VERSION 5.7 ;
  NOWIREEXTENSIONATPIN ON ;
  DIVIDERCHAR "/" ;
  BUSBITCHARS "[]" ;
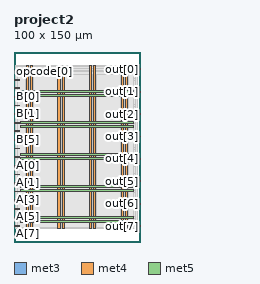
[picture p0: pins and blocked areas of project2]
MACRO project2
  CLASS BLOCK ;
  FOREIGN project2 ;
  ORIGIN 0.000 0.000 ;
  SIZE 100.000 BY 150.000 ;
  PIN A[0]
    DIRECTION INPUT ;
    USE SIGNAL ;
    ANTENNAGATEAREA 0.213000 ;
    PORT
      LAYER met3 ;
        RECT 0.000 59.880 4.000 60.480 ;
    END
  END A[0]
  PIN A[1]
    DIRECTION INPUT ;
    USE SIGNAL ;
    ANTENNAGATEAREA 0.213000 ;
    PORT
      LAYER met3 ;
        RECT 0.000 53.080 4.000 53.680 ;
    END
  END A[1]
  PIN A[2]
    DIRECTION INPUT ;
    USE SIGNAL ;
    ANTENNAGATEAREA 0.213000 ;
    PORT
      LAYER met3 ;
        RECT 0.000 46.280 4.000 46.880 ;
    END
  END A[2]
  PIN A[3]
    DIRECTION INPUT ;
    USE SIGNAL ;
    ANTENNAGATEAREA 0.213000 ;
    PORT
      LAYER met3 ;
        RECT 0.000 39.480 4.000 40.080 ;
    END
  END A[3]
  PIN A[4]
    DIRECTION INPUT ;
    USE SIGNAL ;
    ANTENNAGATEAREA 0.247500 ;
    PORT
      LAYER met3 ;
        RECT 0.000 32.680 4.000 33.280 ;
    END
  END A[4]
  PIN A[5]
    DIRECTION INPUT ;
    USE SIGNAL ;
    ANTENNAGATEAREA 0.247500 ;
    PORT
      LAYER met3 ;
        RECT 0.000 25.880 4.000 26.480 ;
    END
  END A[5]
  PIN A[6]
    DIRECTION INPUT ;
    USE SIGNAL ;
    ANTENNAGATEAREA 0.426000 ;
    PORT
      LAYER met3 ;
        RECT 0.000 19.080 4.000 19.680 ;
    END
  END A[6]
  PIN A[7]
    DIRECTION INPUT ;
    USE SIGNAL ;
    ANTENNAGATEAREA 0.213000 ;
    PORT
      LAYER met3 ;
        RECT 0.000 12.280 4.000 12.880 ;
    END
  END A[7]
  PIN B[0]
    DIRECTION INPUT ;
    USE SIGNAL ;
    ANTENNAGATEAREA 0.742500 ;
    PORT
      LAYER met3 ;
        RECT 0.000 114.280 4.000 114.880 ;
    END
  END B[0]
  PIN B[1]
    DIRECTION INPUT ;
    USE SIGNAL ;
    ANTENNAGATEAREA 0.495000 ;
    PORT
      LAYER met3 ;
        RECT 0.000 107.480 4.000 108.080 ;
    END
  END B[1]
  PIN B[2]
    DIRECTION INPUT ;
    USE SIGNAL ;
    ANTENNAGATEAREA 0.213000 ;
    PORT
      LAYER met3 ;
        RECT 0.000 100.680 4.000 101.280 ;
    END
  END B[2]
  PIN B[3]
    DIRECTION INPUT ;
    USE SIGNAL ;
    ANTENNAGATEAREA 0.213000 ;
    PORT
      LAYER met3 ;
        RECT 0.000 93.880 4.000 94.480 ;
    END
  END B[3]
  PIN B[4]
    DIRECTION INPUT ;
    USE SIGNAL ;
    ANTENNAGATEAREA 0.213000 ;
    PORT
      LAYER met3 ;
        RECT 0.000 87.080 4.000 87.680 ;
    END
  END B[4]
  PIN B[5]
    DIRECTION INPUT ;
    USE SIGNAL ;
    ANTENNAGATEAREA 0.247500 ;
    PORT
      LAYER met3 ;
        RECT 0.000 80.280 4.000 80.880 ;
    END
  END B[5]
  PIN B[6]
    DIRECTION INPUT ;
    USE SIGNAL ;
    ANTENNAGATEAREA 0.247500 ;
    PORT
      LAYER met3 ;
        RECT 0.000 73.480 4.000 74.080 ;
    END
  END B[6]
  PIN B[7]
    DIRECTION INPUT ;
    USE SIGNAL ;
    ANTENNAGATEAREA 0.213000 ;
    PORT
      LAYER met3 ;
        RECT 0.000 66.680 4.000 67.280 ;
    END
  END B[7]
  PIN VGND
    DIRECTION INOUT ;
    USE GROUND ;
    PORT
      LAYER met4 ;
        RECT 13.020 10.640 14.620 138.960 ;
    END
    PORT
      LAYER met4 ;
        RECT 38.020 10.640 39.620 138.960 ;
    END
    PORT
      LAYER met4 ;
        RECT 63.020 10.640 64.620 138.960 ;
    END
    PORT
      LAYER met4 ;
        RECT 88.020 10.640 89.620 138.960 ;
    END
    PORT
      LAYER met5 ;
        RECT 5.280 18.380 94.540 19.980 ;
    END
    PORT
      LAYER met5 ;
        RECT 5.280 43.380 94.540 44.980 ;
    END
    PORT
      LAYER met5 ;
        RECT 5.280 68.380 94.540 69.980 ;
    END
    PORT
      LAYER met5 ;
        RECT 5.280 93.380 94.540 94.980 ;
    END
    PORT
      LAYER met5 ;
        RECT 5.280 118.380 94.540 119.980 ;
    END
  END VGND
  PIN VPWR
    DIRECTION INOUT ;
    USE POWER ;
    PORT
      LAYER met4 ;
        RECT 9.720 10.640 11.320 138.960 ;
    END
    PORT
      LAYER met4 ;
        RECT 34.720 10.640 36.320 138.960 ;
    END
    PORT
      LAYER met4 ;
        RECT 59.720 10.640 61.320 138.960 ;
    END
    PORT
      LAYER met4 ;
        RECT 84.720 10.640 86.320 138.960 ;
    END
    PORT
      LAYER met5 ;
        RECT 5.280 15.080 94.540 16.680 ;
    END
    PORT
      LAYER met5 ;
        RECT 5.280 40.080 94.540 41.680 ;
    END
    PORT
      LAYER met5 ;
        RECT 5.280 65.080 94.540 66.680 ;
    END
    PORT
      LAYER met5 ;
        RECT 5.280 90.080 94.540 91.680 ;
    END
    PORT
      LAYER met5 ;
        RECT 5.280 115.080 94.540 116.680 ;
    END
  END VPWR
  PIN opcode[0]
    DIRECTION INPUT ;
    USE SIGNAL ;
    ANTENNAGATEAREA 0.247500 ;
    PORT
      LAYER met3 ;
        RECT 0.000 134.680 4.000 135.280 ;
    END
  END opcode[0]
  PIN opcode[1]
    DIRECTION INPUT ;
    USE SIGNAL ;
    ANTENNAGATEAREA 0.213000 ;
    PORT
      LAYER met3 ;
        RECT 0.000 127.880 4.000 128.480 ;
    END
  END opcode[1]
  PIN opcode[2]
    DIRECTION INPUT ;
    USE SIGNAL ;
    ANTENNAGATEAREA 0.213000 ;
    PORT
      LAYER met3 ;
        RECT 0.000 121.080 4.000 121.680 ;
    END
  END opcode[2]
  PIN out[0]
    DIRECTION OUTPUT ;
    USE SIGNAL ;
    ANTENNADIFFAREA 0.445500 ;
    PORT
      LAYER met3 ;
        RECT 96.000 136.040 100.000 136.640 ;
    END
  END out[0]
  PIN out[1]
    DIRECTION OUTPUT ;
    USE SIGNAL ;
    ANTENNADIFFAREA 0.445500 ;
    PORT
      LAYER met3 ;
        RECT 96.000 118.360 100.000 118.960 ;
    END
  END out[1]
  PIN out[2]
    DIRECTION OUTPUT ;
    USE SIGNAL ;
    ANTENNADIFFAREA 0.445500 ;
    PORT
      LAYER met3 ;
        RECT 96.000 100.680 100.000 101.280 ;
    END
  END out[2]
  PIN out[3]
    DIRECTION OUTPUT ;
    USE SIGNAL ;
    ANTENNADIFFAREA 0.445500 ;
    PORT
      LAYER met3 ;
        RECT 96.000 83.000 100.000 83.600 ;
    END
  END out[3]
  PIN out[4]
    DIRECTION OUTPUT ;
    USE SIGNAL ;
    ANTENNADIFFAREA 0.445500 ;
    PORT
      LAYER met3 ;
        RECT 96.000 65.320 100.000 65.920 ;
    END
  END out[4]
  PIN out[5]
    DIRECTION OUTPUT ;
    USE SIGNAL ;
    ANTENNADIFFAREA 0.891000 ;
    PORT
      LAYER met3 ;
        RECT 96.000 47.640 100.000 48.240 ;
    END
  END out[5]
  PIN out[6]
    DIRECTION OUTPUT ;
    USE SIGNAL ;
    ANTENNADIFFAREA 0.891000 ;
    PORT
      LAYER met3 ;
        RECT 96.000 29.960 100.000 30.560 ;
    END
  END out[6]
  PIN out[7]
    DIRECTION OUTPUT ;
    USE SIGNAL ;
    ANTENNADIFFAREA 1.336500 ;
    PORT
      LAYER met3 ;
        RECT 96.000 12.280 100.000 12.880 ;
    END
  END out[7]
  OBS
      LAYER nwell ;
        RECT 5.330 10.795 94.490 138.910 ;
      LAYER li1 ;
        RECT 5.520 10.795 94.300 138.805 ;
      LAYER met1 ;
        RECT 1.450 10.640 97.450 138.960 ;
      LAYER met2 ;
        RECT 1.480 10.695 97.420 138.905 ;
      LAYER met3 ;
        RECT 3.030 137.040 96.075 138.885 ;
        RECT 3.030 135.680 95.600 137.040 ;
        RECT 4.400 135.640 95.600 135.680 ;
        RECT 4.400 134.280 96.075 135.640 ;
        RECT 3.030 128.880 96.075 134.280 ;
        RECT 4.400 127.480 96.075 128.880 ;
        RECT 3.030 122.080 96.075 127.480 ;
        RECT 4.400 120.680 96.075 122.080 ;
        RECT 3.030 119.360 96.075 120.680 ;
        RECT 3.030 117.960 95.600 119.360 ;
        RECT 3.030 115.280 96.075 117.960 ;
        RECT 4.400 113.880 96.075 115.280 ;
        RECT 3.030 108.480 96.075 113.880 ;
        RECT 4.400 107.080 96.075 108.480 ;
        RECT 3.030 101.680 96.075 107.080 ;
        RECT 4.400 100.280 95.600 101.680 ;
        RECT 3.030 94.880 96.075 100.280 ;
        RECT 4.400 93.480 96.075 94.880 ;
        RECT 3.030 88.080 96.075 93.480 ;
        RECT 4.400 86.680 96.075 88.080 ;
        RECT 3.030 84.000 96.075 86.680 ;
        RECT 3.030 82.600 95.600 84.000 ;
        RECT 3.030 81.280 96.075 82.600 ;
        RECT 4.400 79.880 96.075 81.280 ;
        RECT 3.030 74.480 96.075 79.880 ;
        RECT 4.400 73.080 96.075 74.480 ;
        RECT 3.030 67.680 96.075 73.080 ;
        RECT 4.400 66.320 96.075 67.680 ;
        RECT 4.400 66.280 95.600 66.320 ;
        RECT 3.030 64.920 95.600 66.280 ;
        RECT 3.030 60.880 96.075 64.920 ;
        RECT 4.400 59.480 96.075 60.880 ;
        RECT 3.030 54.080 96.075 59.480 ;
        RECT 4.400 52.680 96.075 54.080 ;
        RECT 3.030 48.640 96.075 52.680 ;
        RECT 3.030 47.280 95.600 48.640 ;
        RECT 4.400 47.240 95.600 47.280 ;
        RECT 4.400 45.880 96.075 47.240 ;
        RECT 3.030 40.480 96.075 45.880 ;
        RECT 4.400 39.080 96.075 40.480 ;
        RECT 3.030 33.680 96.075 39.080 ;
        RECT 4.400 32.280 96.075 33.680 ;
        RECT 3.030 30.960 96.075 32.280 ;
        RECT 3.030 29.560 95.600 30.960 ;
        RECT 3.030 26.880 96.075 29.560 ;
        RECT 4.400 25.480 96.075 26.880 ;
        RECT 3.030 20.080 96.075 25.480 ;
        RECT 4.400 18.680 96.075 20.080 ;
        RECT 3.030 13.280 96.075 18.680 ;
        RECT 4.400 11.880 95.600 13.280 ;
        RECT 3.030 10.715 96.075 11.880 ;
      LAYER met4 ;
        RECT 3.055 11.735 9.320 132.425 ;
        RECT 11.720 11.735 12.620 132.425 ;
        RECT 15.020 11.735 34.320 132.425 ;
        RECT 36.720 11.735 37.620 132.425 ;
        RECT 40.020 11.735 59.320 132.425 ;
        RECT 61.720 11.735 62.620 132.425 ;
        RECT 65.020 11.735 84.320 132.425 ;
        RECT 86.720 11.735 87.620 132.425 ;
        RECT 90.020 11.735 94.465 132.425 ;
  END
END project2
END LIBRARY

